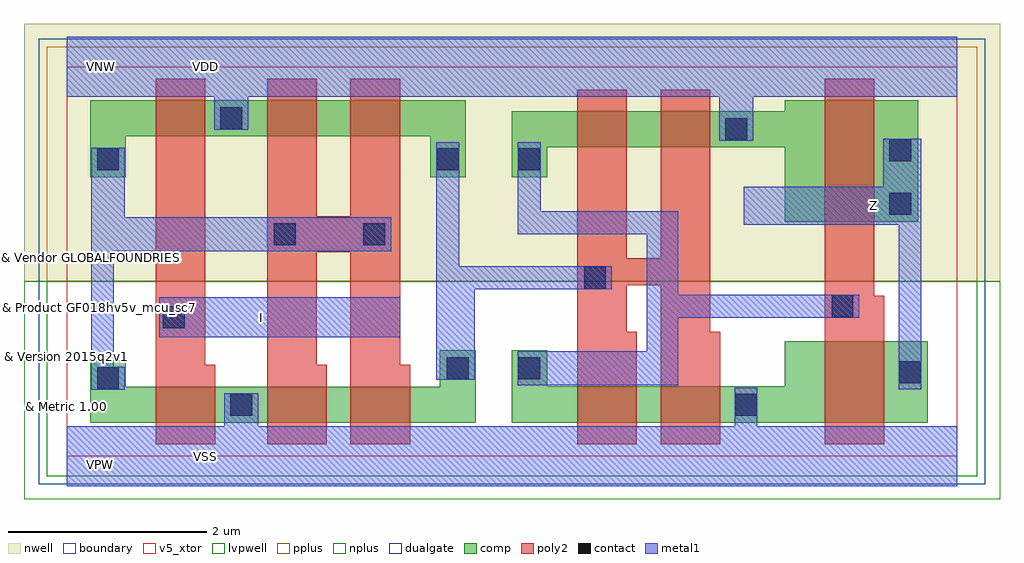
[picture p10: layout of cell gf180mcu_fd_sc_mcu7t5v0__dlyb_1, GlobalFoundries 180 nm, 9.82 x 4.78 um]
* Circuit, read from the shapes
.subckt gf180mcu_fd_sc_mcu7t5v0__dlyb_1 I VDD VNW VSS Z
XM1 VSS I n1 VSUBS nfet_05v0 w=0.36u l=0.6u
XM2 n2 n1 VSS VSUBS nfet_05v0 w=0.36u l=0.6u
XM3 n3 n1 n2 VSUBS nfet_05v0 w=0.36u l=0.6u
XM4 n4 n3 n5 VSUBS nfet_05v0 w=0.365u l=0.6u
XM5 VSS n3 n4 VSUBS nfet_05v0 w=0.365u l=0.6u
XM6 Z n5 VSS VSUBS nfet_05v0 w=0.82u l=0.6u
XM7 VDD I n1 VNW pfet_05v0 w=0.36u l=0.5u
XM8 n6 n1 VDD VNW pfet_05v0 w=0.36u l=0.5u
XM9 n3 n1 n6 VNW pfet_05v0 w=0.36u l=0.5u
XM10 n7 n3 n5 VNW pfet_05v0 w=0.36u l=0.5u
XM11 VDD n3 n7 VNW pfet_05v0 w=0.36u l=0.5u
XM12 Z n5 VDD VNW pfet_05v0 w=1.22u l=0.5u
.ends

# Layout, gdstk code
import gdstk
lib = gdstk.Library(unit=1e-6, precision=1e-09)
def R(c, l, rs):  # rectangles x0, y0, x1, y1
    for r in rs: c.add(gdstk.rectangle(r[:2], r[2:], *l))
def P(c, l, *ps):  # polygons
    for p in ps: c.add(gdstk.Polygon(p, *l))
boundary = (0, 0)
nwell = (21, 0)
comp = (22, 0)
poly2 = (30, 0)
pplus = (31, 0)
nplus = (32, 0)
contact = (33, 0)
metal1 = (34, 0)
dualgate = (55, 0)
v5_xtor = (112, 1)
lvpwell = (204, 0)

gf180mcu_fd_sc_mcu7t5v0_ = lib.new_cell('gf180mcu_fd_sc_mcu7t5v0__dlyb_1')
R(gf180mcu_fd_sc_mcu7t5v0_, boundary, [(0,0,8.96,3.92)])
R(gf180mcu_fd_sc_mcu7t5v0_, nwell, [(-0.43,1.76,9.39,4.35)])
P(gf180mcu_fd_sc_mcu7t5v0_, comp, [(0.235,2.81),(0.235,3.58),(4.015,3.58),(4.015,2.81),(3.655,2.81),(3.655,3.22),(0.595,3.22),(0.595,2.81)],
  [(0.235,0.34),(0.235,0.965),(0.595,0.965),(0.595,0.7),(3.755,0.7),(3.755,1.065),(4.115,1.065),(4.115,0.34)],
  [(7.225,2.36),(7.225,3.11),(4.835,3.11),(4.835,2.81),(4.475,2.81),(4.475,3.47),(7.225,3.47),(7.225,3.58),(8.565,3.58),(8.565,2.36)],
  [(4.475,0.34),(4.475,1.065),(4.835,1.065),(4.835,0.705),(7.225,0.705),(7.225,1.16),(8.665,1.16),(8.665,0.34)])
P(gf180mcu_fd_sc_mcu7t5v0_, poly2, [(0.895,0.12),(0.895,3.8),(1.395,3.8),(1.395,0.92),(1.495,0.92),(1.495,0.12)],
  [(2.015,0.12),(2.015,3.8),(2.515,3.8),(2.515,2.415),(2.855,2.415),(2.855,3.8),(3.355,3.8),(3.355,0.92),(3.455,0.92),(3.455,0.12),(2.855,0.12),(2.855,2.055),(2.515,2.055),(2.515,0.92),(2.615,0.92),(2.615,0.12)],
  [(5.135,0.12),(5.135,3.69),(5.635,3.69),(5.635,1.995),(5.975,1.995),(5.975,3.69),(6.475,3.69),(6.475,1.255),(6.575,1.255),(6.575,0.12),(5.975,0.12),(5.975,1.72),(5.635,1.72),(5.635,1.255),(5.735,1.255),(5.735,0.12)],
  [(7.625,0.12),(7.625,3.8),(8.125,3.8),(8.125,1.615),(8.225,1.615),(8.225,0.12)])
R(gf180mcu_fd_sc_mcu7t5v0_, pplus, [(-0.2,1.76,9.16,4.12)])
R(gf180mcu_fd_sc_mcu7t5v0_, nplus, [(-0.2,-0.2,9.16,1.76)])
R(gf180mcu_fd_sc_mcu7t5v0_, contact, [(1.645,0.41,1.865,0.63), (6.725,0.41,6.945,0.63), (0.305,0.675,0.525,0.895), (8.375,0.735,8.595,0.955), (3.825,0.775,4.045,0.995), (4.545,0.775,4.765,0.995), (0.965,1.29,1.185,1.51), (7.695,1.4,7.915,1.62), (5.205,1.685,5.425,1.905), (2.085,2.125,2.305,2.345), (2.985,2.125,3.205,2.345), (8.275,2.43,8.495,2.65), (0.305,2.88,0.525,3.1), (3.725,2.88,3.945,3.1), (4.545,2.88,4.765,3.1), (8.275,2.97,8.495,3.19), (6.625,3.18,6.845,3.4), (1.545,3.29,1.765,3.51)])
R(gf180mcu_fd_sc_mcu7t5v0_, metal1, [(0.93,1.2,3.355,1.6)])
P(gf180mcu_fd_sc_mcu7t5v0_, metal1, [(0.245,0.67),(0.245,3.105),(0.585,3.105),(0.585,2.405),(3.265,2.405),(3.265,2.065),(0.475,2.065),(0.475,0.9),(0.585,0.9),(0.585,0.67)],
  [(3.72,0.77),(3.72,3.16),(3.95,3.16),(3.95,1.91),(5.485,1.91),(5.485,1.68),(4.105,1.68),(4.105,0.77)],
  [(4.54,0.715),(4.54,1.055),(5.835,1.055),(5.835,2.235),(4.54,2.235),(4.54,3.16),(4.77,3.16),(4.77,2.465),(6.155,2.465),(6.155,1.625),(7.975,1.625),(7.975,1.395),(6.155,1.395),(6.155,0.715)],
  [(8.37,0.675),(8.37,2.33),(6.81,2.33),(6.81,2.71),(8.215,2.71),(8.215,3.195),(8.6,3.195),(8.6,0.675)],
  [(0,-0.3),(0,0.3),(1.585,0.3),(1.585,0.635),(1.925,0.635),(1.925,0.3),(6.72,0.3),(6.72,0.69),(6.95,0.69),(6.95,0.3),(8.96,0.3),(8.96,-0.3)],
  [(6.565,3.175),(6.565,3.62),(1.825,3.62),(1.825,3.285),(1.485,3.285),(1.485,3.62),(0,3.62),(0,4.22),(8.96,4.22),(8.96,3.62),(6.905,3.62),(6.905,3.175)])
R(gf180mcu_fd_sc_mcu7t5v0_, dualgate, [(-0.28,-0.28,9.24,4.2)])
R(gf180mcu_fd_sc_mcu7t5v0_, v5_xtor, [(0,0,8.96,3.92)])
R(gf180mcu_fd_sc_mcu7t5v0_, lvpwell, [(-0.43,-0.43,9.39,1.76)])
gf180mcu_fd_sc_mcu7t5v0_.add(gdstk.Label('VDD', (1.4,3.92), layer=34, texttype=10))
gf180mcu_fd_sc_mcu7t5v0_.add(gdstk.Label('I', (1.96,1.4), layer=34, texttype=10))
gf180mcu_fd_sc_mcu7t5v0_.add(gdstk.Label('VSS', (1.4,0), layer=34, texttype=10))
gf180mcu_fd_sc_mcu7t5v0_.add(gdstk.Label('Z', (8.12,2.52), layer=34, texttype=10))
gf180mcu_fd_sc_mcu7t5v0_.add(gdstk.Label('& Vendor GLOBALFOUNDRIES', (0,2), layer=63, texttype=63))
gf180mcu_fd_sc_mcu7t5v0_.add(gdstk.Label('& Product GF018hv5v_mcu_sc7', (0,1.5), layer=63, texttype=63))
gf180mcu_fd_sc_mcu7t5v0_.add(gdstk.Label('& Version 2015q2v1', (0,1), layer=63, texttype=63))
gf180mcu_fd_sc_mcu7t5v0_.add(gdstk.Label('& Metric 1.00', (0,0.5), layer=63, texttype=63))
gf180mcu_fd_sc_mcu7t5v0_.add(gdstk.Label('VNW', (0.345,3.92), layer=21, texttype=10))
gf180mcu_fd_sc_mcu7t5v0_.add(gdstk.Label('VPW', (0.34,-0.085), layer=204, texttype=10))

lib.write_gds('gf180mcu_fd_sc_mcu7t5v0__dlyb_1.gds')
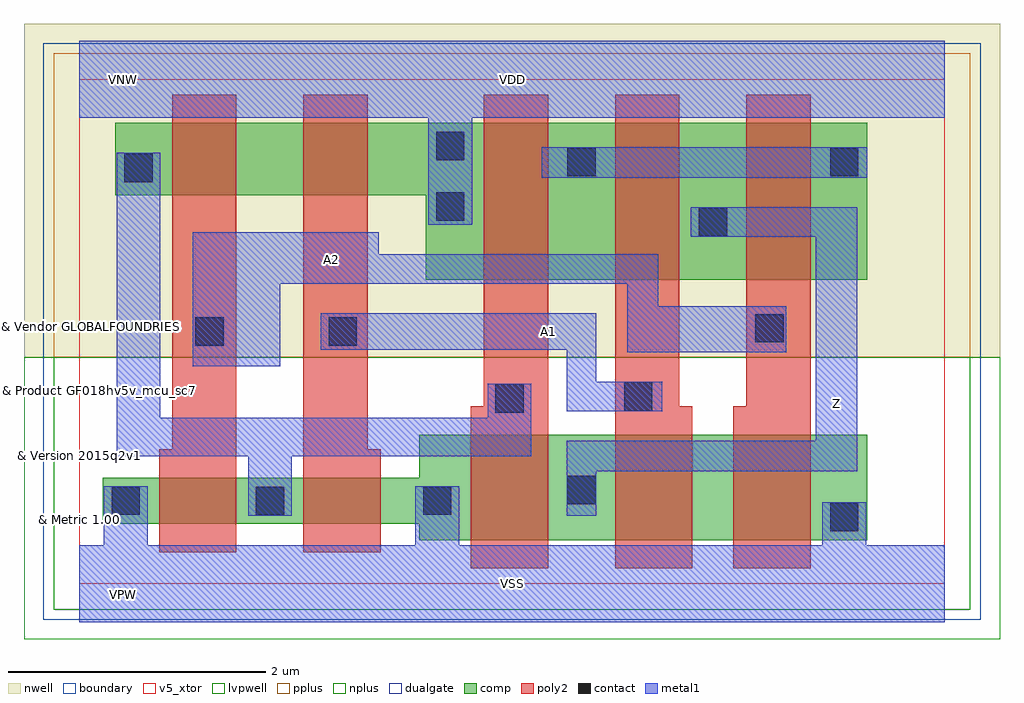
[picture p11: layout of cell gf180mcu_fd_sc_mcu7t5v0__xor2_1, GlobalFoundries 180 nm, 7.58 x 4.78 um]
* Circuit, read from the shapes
.subckt gf180mcu_fd_sc_mcu7t5v0__xor2_1 A1 A2 VDD VNW VSS Z
XM1 n1 A2 VSS VSUBS nfet_05v0 w=0.36u l=0.6u
XM2 VSS A1 n1 VSUBS nfet_05v0 w=0.36u l=0.6u
XM3 Z n1 VSS VSUBS nfet_05v0 w=0.82u l=0.6u
XM4 n2 A1 Z VSUBS nfet_05v0 w=0.82u l=0.6u
XM5 VSS A2 n2 VSUBS nfet_05v0 w=0.82u l=0.6u
XM6 n3 A2 n1 VNW pfet_05v0 w=0.56u l=0.5u
XM7 VDD A1 n3 VNW pfet_05v0 w=0.56u l=0.5u
XM8 n4 n1 VDD VNW pfet_05v0 w=1.22u l=0.5u
XM9 Z A1 n4 VNW pfet_05v0 w=1.22u l=0.5u
XM10 n4 A2 Z VNW pfet_05v0 w=1.22u l=0.5u
.ends

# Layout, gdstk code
import gdstk
lib = gdstk.Library(unit=1e-6, precision=1e-09)
def R(c, l, rs):  # rectangles x0, y0, x1, y1
    for r in rs: c.add(gdstk.rectangle(r[:2], r[2:], *l))
def P(c, l, *ps):  # polygons
    for p in ps: c.add(gdstk.Polygon(p, *l))
boundary = (0, 0)
nwell = (21, 0)
comp = (22, 0)
poly2 = (30, 0)
pplus = (31, 0)
nplus = (32, 0)
contact = (33, 0)
metal1 = (34, 0)
dualgate = (55, 0)
v5_xtor = (112, 1)
lvpwell = (204, 0)

gf180mcu_fd_sc_mcu7t5v0_ = lib.new_cell('gf180mcu_fd_sc_mcu7t5v0__xor2_1')
R(gf180mcu_fd_sc_mcu7t5v0_, boundary, [(0,0,6.72,3.92)])
R(gf180mcu_fd_sc_mcu7t5v0_, nwell, [(-0.43,1.76,7.15,4.35)])
P(gf180mcu_fd_sc_mcu7t5v0_, comp, [(2.64,0.34),(2.64,0.465),(0.18,0.465),(0.18,0.825),(2.64,0.825),(2.64,1.16),(6.12,1.16),(6.12,0.34)],
  [(2.69,2.36),(2.69,3.02),(0.28,3.02),(0.28,3.58),(6.12,3.58),(6.12,2.36)])
P(gf180mcu_fd_sc_mcu7t5v0_, poly2, [(0.62,0.245),(0.62,1.045),(0.72,1.045),(0.72,3.8),(1.22,3.8),(1.22,0.245)],
  [(1.74,0.245),(1.74,3.8),(2.24,3.8),(2.24,1.045),(2.34,1.045),(2.34,0.245)],
  [(3.04,0.12),(3.04,1.38),(3.14,1.38),(3.14,3.8),(3.64,3.8),(3.64,0.12)],
  [(4.16,0.12),(4.16,3.8),(4.66,3.8),(4.66,1.38),(4.76,1.38),(4.76,0.12)],
  [(5.08,0.12),(5.08,1.38),(5.18,1.38),(5.18,3.8),(5.68,3.8),(5.68,0.12)])
R(gf180mcu_fd_sc_mcu7t5v0_, pplus, [(-0.2,1.76,6.92,4.12)])
R(gf180mcu_fd_sc_mcu7t5v0_, nplus, [(-0.2,-0.2,6.92,1.76)])
R(gf180mcu_fd_sc_mcu7t5v0_, contact, [(5.83,0.41,6.05,0.63), (0.25,0.535,0.47,0.755), (1.37,0.535,1.59,0.755), (2.67,0.535,2.89,0.755), (3.79,0.62,4.01,0.84), (3.23,1.33,3.45,1.55), (4.23,1.345,4.45,1.565), (0.9,1.85,1.12,2.07), (1.935,1.85,2.155,2.07), (5.25,1.875,5.47,2.095), (4.81,2.7,5.03,2.92), (2.77,2.82,2.99,3.04), (0.35,3.12,0.57,3.34), (3.79,3.165,4.01,3.385), (5.83,3.165,6.05,3.385), (2.77,3.29,2.99,3.51)])
R(gf180mcu_fd_sc_mcu7t5v0_, metal1, [(3.59,3.155,6.12,3.39)])
P(gf180mcu_fd_sc_mcu7t5v0_, metal1, [(1.31,0.53),(1.31,0.99),(0.29,0.99),(0.29,3.35),(0.63,3.35),(0.63,1.29),(3.17,1.29),(3.17,1.555),(3.51,1.555),(3.51,0.99),(1.65,0.99),(1.65,0.53)],
  [(3.785,1.34),(3.785,1.82),(1.875,1.82),(1.875,2.1),(4.015,2.1),(4.015,1.57),(4.525,1.57),(4.525,1.34)],
  [(0.88,1.69),(0.88,2.73),(2.325,2.73),(2.325,2.56),(4.495,2.56),(4.495,2.155),(5.49,2.155),(5.49,1.8),(4.255,1.8),(4.255,2.33),(1.56,2.33),(1.56,1.69)],
  [(3.785,0.53),(3.785,1.11),(5.72,1.11),(5.72,2.695),(4.75,2.695),(4.75,2.925),(6.04,2.925),(6.04,0.875),(4.015,0.875),(4.015,0.53)],
  [(0,-0.3),(0,0.3),(0.19,0.3),(0.19,0.76),(0.53,0.76),(0.53,0.3),(2.61,0.3),(2.61,0.76),(2.95,0.76),(2.95,0.3),(5.77,0.3),(5.77,0.635),(6.11,0.635),(6.11,0.3),(6.72,0.3),(6.72,-0.3)],
  [(2.71,2.79),(2.71,3.62),(0,3.62),(0,4.22),(6.72,4.22),(6.72,3.62),(3.05,3.62),(3.05,2.79)])
R(gf180mcu_fd_sc_mcu7t5v0_, dualgate, [(-0.28,-0.28,7,4.2)])
R(gf180mcu_fd_sc_mcu7t5v0_, v5_xtor, [(0,0,6.72,3.92)])
R(gf180mcu_fd_sc_mcu7t5v0_, lvpwell, [(-0.43,-0.43,7.15,1.76)])
gf180mcu_fd_sc_mcu7t5v0_.add(gdstk.Label('VDD', (3.36,3.915), layer=34, texttype=10))
gf180mcu_fd_sc_mcu7t5v0_.add(gdstk.Label('VSS', (3.36,0), layer=34, texttype=10))
gf180mcu_fd_sc_mcu7t5v0_.add(gdstk.Label('Z', (5.88,1.4), layer=34, texttype=10))
gf180mcu_fd_sc_mcu7t5v0_.add(gdstk.Label('A1', (3.64,1.96), layer=34, texttype=10))
gf180mcu_fd_sc_mcu7t5v0_.add(gdstk.Label('A2', (1.96,2.52), layer=34, texttype=10))
gf180mcu_fd_sc_mcu7t5v0_.add(gdstk.Label('& Vendor GLOBALFOUNDRIES', (0,2), layer=63, texttype=63))
gf180mcu_fd_sc_mcu7t5v0_.add(gdstk.Label('& Product GF018hv5v_mcu_sc7', (0,1.5), layer=63, texttype=63))
gf180mcu_fd_sc_mcu7t5v0_.add(gdstk.Label('& Version 2015q2v1', (0,1), layer=63, texttype=63))
gf180mcu_fd_sc_mcu7t5v0_.add(gdstk.Label('& Metric 1.00', (0,0.5), layer=63, texttype=63))
gf180mcu_fd_sc_mcu7t5v0_.add(gdstk.Label('VNW', (0.345,3.92), layer=21, texttype=10))
gf180mcu_fd_sc_mcu7t5v0_.add(gdstk.Label('VPW', (0.34,-0.085), layer=204, texttype=10))

lib.write_gds('gf180mcu_fd_sc_mcu7t5v0__xor2_1.gds')
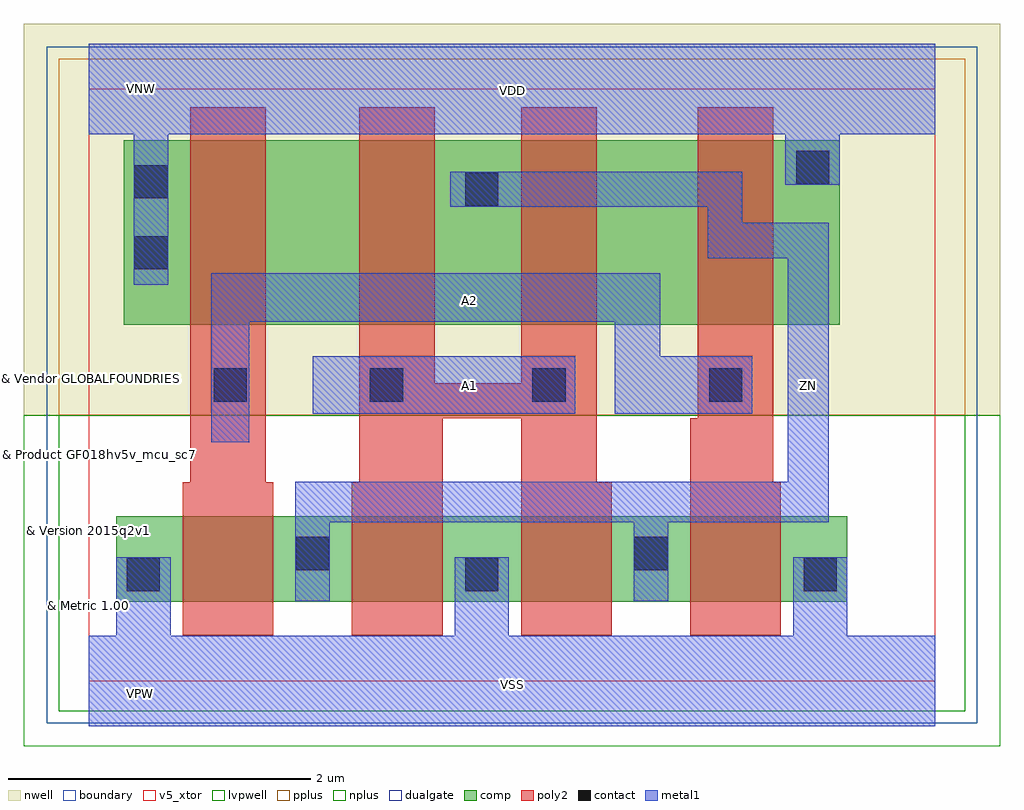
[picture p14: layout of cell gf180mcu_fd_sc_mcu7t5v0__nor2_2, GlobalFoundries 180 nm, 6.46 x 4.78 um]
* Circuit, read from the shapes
.subckt gf180mcu_fd_sc_mcu7t5v0__nor2_2 A1 A2 VDD VNW VSS ZN
XM1 ZN A2 VSS VSUBS nfet_05v0 w=0.565u l=0.6u m=2
XM2 VSS A1 ZN VSUBS nfet_05v0 w=0.565u l=0.6u m=2
XM3 n1 A2 VDD VNW pfet_05v0 w=1.22u l=0.5u
XM4 ZN A1 n1 VNW pfet_05v0 w=1.22u l=0.5u
XM5 n2 A1 ZN VNW pfet_05v0 w=1.22u l=0.5u
XM6 VDD A2 n2 VNW pfet_05v0 w=1.22u l=0.5u
.ends

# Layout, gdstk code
import gdstk
lib = gdstk.Library(unit=1e-6, precision=1e-09)
def R(c, l, rs):  # rectangles x0, y0, x1, y1
    for r in rs: c.add(gdstk.rectangle(r[:2], r[2:], *l))
def A(c, l, x, y, w, h, nx, ny, dx, dy):  # array of equal rectangles
    R(c, l, [(x+i*dx, y+j*dy, x+i*dx+w, y+j*dy+h) for i in range(nx) for j in range(ny)])
def P(c, l, *ps):  # polygons
    for p in ps: c.add(gdstk.Polygon(p, *l))
boundary = (0, 0)
nwell = (21, 0)
comp = (22, 0)
poly2 = (30, 0)
pplus = (31, 0)
nplus = (32, 0)
contact = (33, 0)
metal1 = (34, 0)
dualgate = (55, 0)
v5_xtor = (112, 1)
lvpwell = (204, 0)

gf180mcu_fd_sc_mcu7t5v0_ = lib.new_cell('gf180mcu_fd_sc_mcu7t5v0__nor2_2')
R(gf180mcu_fd_sc_mcu7t5v0_, boundary, [(0,0,5.6,3.92)])
R(gf180mcu_fd_sc_mcu7t5v0_, nwell, [(-0.43,1.76,6.03,4.35)])
R(gf180mcu_fd_sc_mcu7t5v0_, comp, [(0.18,0.525,5.02,1.09), (0.23,2.36,4.97,3.58)])
P(gf180mcu_fd_sc_mcu7t5v0_, poly2, [(0.62,0.305),(0.62,1.315),(0.67,1.315),(0.67,3.8),(1.17,3.8),(1.17,1.315),(1.22,1.315),(1.22,0.305)],
  [(1.74,0.305),(1.74,1.315),(1.79,1.315),(1.79,3.8),(2.29,3.8),(2.29,1.97),(2.86,1.97),(2.86,3.8),(3.36,3.8),(3.36,1.315),(3.46,1.315),(3.46,0.305),(2.86,0.305),(2.86,1.74),(2.34,1.74),(2.34,0.305)],
  [(3.98,0.305),(3.98,1.74),(4.03,1.74),(4.03,3.8),(4.53,3.8),(4.53,1.315),(4.58,1.315),(4.58,0.305)])
R(gf180mcu_fd_sc_mcu7t5v0_, pplus, [(-0.2,1.76,5.8,4.12)])
R(gf180mcu_fd_sc_mcu7t5v0_, nplus, [(-0.2,-0.2,5.8,1.76)])
A(gf180mcu_fd_sc_mcu7t5v0_, contact, 0.25, 0.595, 0.22, 0.22, 3, 1, 2.24, 0)
R(gf180mcu_fd_sc_mcu7t5v0_, contact, [(1.37,0.735,1.59,0.955), (3.61,0.735,3.83,0.955), (0.825,1.85,1.045,2.07), (1.86,1.85,2.08,2.07), (2.935,1.85,3.155,2.07), (4.105,1.85,4.325,2.07), (0.3,2.725,0.52,2.945), (2.49,3.145,2.71,3.365), (0.3,3.195,0.52,3.415), (4.68,3.29,4.9,3.51)])
R(gf180mcu_fd_sc_mcu7t5v0_, metal1, [(1.48,1.77,3.22,2.15)])
P(gf180mcu_fd_sc_mcu7t5v0_, metal1, [(0.81,1.58),(0.81,2.7),(3.78,2.7),(3.78,2.15),(4.39,2.15),(4.39,1.77),(3.48,1.77),(3.48,2.38),(1.06,2.38),(1.06,1.58)],
  [(1.365,0.53),(1.365,1.32),(4.625,1.32),(4.625,2.8),(4.095,2.8),(4.095,3.14),(2.39,3.14),(2.39,3.37),(4.325,3.37),(4.325,3.035),(4.895,3.035),(4.895,1.05),(3.835,1.05),(3.835,0.53),(3.605,0.53),(3.605,1.05),(1.595,1.05),(1.595,0.53)],
  [(0,-0.3),(0,0.3),(0.18,0.3),(0.18,0.82),(0.54,0.82),(0.54,0.3),(2.42,0.3),(2.42,0.82),(2.78,0.82),(2.78,0.3),(4.66,0.3),(4.66,0.82),(5.02,0.82),(5.02,0.3),(5.6,0.3),(5.6,-0.3)],
  [(0.295,2.625),(0.295,3.62),(0,3.62),(0,4.22),(5.6,4.22),(5.6,3.62),(4.97,3.62),(4.97,3.285),(4.61,3.285),(4.61,3.62),(0.525,3.62),(0.525,2.625)])
R(gf180mcu_fd_sc_mcu7t5v0_, dualgate, [(-0.28,-0.28,5.88,4.2)])
R(gf180mcu_fd_sc_mcu7t5v0_, v5_xtor, [(0,0,5.6,3.92)])
R(gf180mcu_fd_sc_mcu7t5v0_, lvpwell, [(-0.43,-0.43,6.03,1.76)])
gf180mcu_fd_sc_mcu7t5v0_.add(gdstk.Label('VDD', (2.8,3.91), layer=34, texttype=10))
gf180mcu_fd_sc_mcu7t5v0_.add(gdstk.Label('VSS', (2.8,-0.025), layer=34, texttype=10))
gf180mcu_fd_sc_mcu7t5v0_.add(gdstk.Label('ZN', (4.76,1.96), layer=34, texttype=10))
gf180mcu_fd_sc_mcu7t5v0_.add(gdstk.Label('A1', (2.52,1.96), layer=34, texttype=10))
gf180mcu_fd_sc_mcu7t5v0_.add(gdstk.Label('A2', (2.52,2.52), layer=34, texttype=10))
gf180mcu_fd_sc_mcu7t5v0_.add(gdstk.Label('& Vendor GLOBALFOUNDRIES', (0,2), layer=63, texttype=63))
gf180mcu_fd_sc_mcu7t5v0_.add(gdstk.Label('& Product GF018hv5v_mcu_sc7', (0,1.5), layer=63, texttype=63))
gf180mcu_fd_sc_mcu7t5v0_.add(gdstk.Label('& Version 2015q2v1', (0,1), layer=63, texttype=63))
gf180mcu_fd_sc_mcu7t5v0_.add(gdstk.Label('& Metric 1.00', (0,0.5), layer=63, texttype=63))
gf180mcu_fd_sc_mcu7t5v0_.add(gdstk.Label('VNW', (0.345,3.92), layer=21, texttype=10))
gf180mcu_fd_sc_mcu7t5v0_.add(gdstk.Label('VPW', (0.34,-0.085), layer=204, texttype=10))

lib.write_gds('gf180mcu_fd_sc_mcu7t5v0__nor2_2.gds')
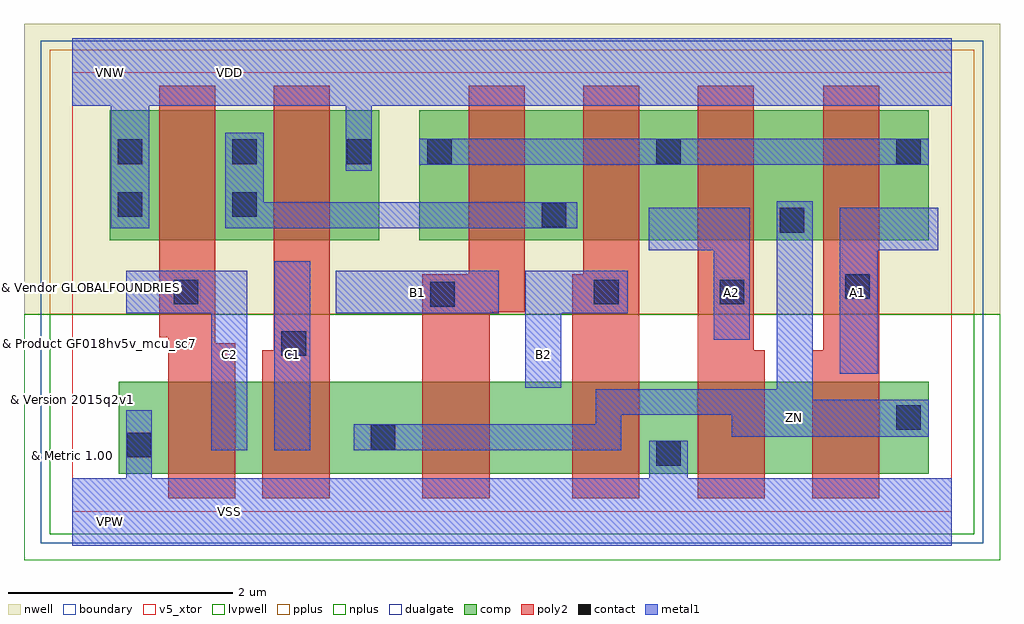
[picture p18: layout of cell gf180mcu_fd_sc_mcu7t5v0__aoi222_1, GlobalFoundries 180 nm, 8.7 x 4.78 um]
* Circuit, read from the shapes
.subckt gf180mcu_fd_sc_mcu7t5v0__aoi222_1 A1 A2 B1 B2 C1 C2 VDD VNW VSS ZN
XM1 n1 C2 VSS VSUBS nfet_05v0 w=0.82u l=0.6u
XM2 ZN C1 n1 VSUBS nfet_05v0 w=0.82u l=0.6u
XM3 n2 B1 ZN VSUBS nfet_05v0 w=0.82u l=0.6u
XM4 VSS B2 n2 VSUBS nfet_05v0 w=0.82u l=0.6u
XM5 n3 A2 VSS VSUBS nfet_05v0 w=0.82u l=0.6u
XM6 ZN A1 n3 VSUBS nfet_05v0 w=0.82u l=0.6u
XM7 n4 C2 VDD VNW pfet_05v0 w=1.16u l=0.5u
XM8 VDD C1 n4 VNW pfet_05v0 w=1.16u l=0.5u
XM9 n4 B1 n5 VNW pfet_05v0 w=1.16u l=0.5u
XM10 n5 B2 n4 VNW pfet_05v0 w=1.16u l=0.5u
XM11 ZN A2 n5 VNW pfet_05v0 w=1.16u l=0.5u
XM12 n5 A1 ZN VNW pfet_05v0 w=1.16u l=0.5u
.ends

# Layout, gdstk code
import gdstk
lib = gdstk.Library(unit=1e-6, precision=1e-09)
def R(c, l, rs):  # rectangles x0, y0, x1, y1
    for r in rs: c.add(gdstk.rectangle(r[:2], r[2:], *l))
def A(c, l, x, y, w, h, nx, ny, dx, dy):  # array of equal rectangles
    R(c, l, [(x+i*dx, y+j*dy, x+i*dx+w, y+j*dy+h) for i in range(nx) for j in range(ny)])
def P(c, l, *ps):  # polygons
    for p in ps: c.add(gdstk.Polygon(p, *l))
boundary = (0, 0)
nwell = (21, 0)
comp = (22, 0)
poly2 = (30, 0)
pplus = (31, 0)
nplus = (32, 0)
contact = (33, 0)
metal1 = (34, 0)
dualgate = (55, 0)
v5_xtor = (112, 1)
lvpwell = (204, 0)

gf180mcu_fd_sc_mcu7t5v0_ = lib.new_cell('gf180mcu_fd_sc_mcu7t5v0__aoi222_1')
R(gf180mcu_fd_sc_mcu7t5v0_, boundary, [(0,0,7.84,3.92)])
R(gf180mcu_fd_sc_mcu7t5v0_, nwell, [(-0.43,1.76,8.27,4.35)])
R(gf180mcu_fd_sc_mcu7t5v0_, comp, [(0.415,0.34,7.635,1.16), (0.335,2.42,2.735,3.58), (3.095,2.42,7.635,3.58)])
P(gf180mcu_fd_sc_mcu7t5v0_, poly2, [(0.855,0.12),(0.855,1.555),(0.775,1.555),(0.775,3.8),(1.275,3.8),(1.275,1.505),(1.455,1.505),(1.455,0.12)],
  [(1.695,0.12),(1.695,1.44),(1.795,1.44),(1.795,3.8),(2.295,3.8),(2.295,0.12)],
  [(3.12,0.12),(3.12,2.12),(3.535,2.12),(3.535,3.8),(4.035,3.8),(4.035,1.78),(3.72,1.78),(3.72,0.12)],
  [(4.455,0.12),(4.455,2.12),(4.555,2.12),(4.555,3.8),(5.055,3.8),(5.055,0.12)],
  [(5.575,0.12),(5.575,3.8),(6.075,3.8),(6.075,1.44),(6.175,1.44),(6.175,0.12)],
  [(6.595,0.12),(6.595,1.44),(6.695,1.44),(6.695,3.8),(7.195,3.8),(7.195,0.12)])
R(gf180mcu_fd_sc_mcu7t5v0_, pplus, [(-0.2,1.76,8.04,4.12)])
R(gf180mcu_fd_sc_mcu7t5v0_, nplus, [(-0.2,-0.2,8.04,1.76)])
A(gf180mcu_fd_sc_mcu7t5v0_, contact, 0.405, 3.1, 0.22, 0.22, 3, 1, 1.02, 0)
R(gf180mcu_fd_sc_mcu7t5v0_, contact, [(5.205,0.41,5.425,0.63), (0.485,0.485,0.705,0.705), (2.66,0.555,2.88,0.775), (7.345,0.73,7.565,0.95), (1.865,1.39,2.085,1.61), (3.19,1.83,3.41,2.05), (0.905,1.85,1.125,2.07), (4.65,1.85,4.87,2.07), (5.77,1.85,5.99,2.07), (6.89,1.9,7.11,2.12), (6.305,2.49,6.525,2.71), (4.185,2.535,4.405,2.755), (0.405,2.63,0.625,2.85), (1.425,2.63,1.645,2.85), (3.165,3.1,3.385,3.32), (5.205,3.1,5.425,3.32), (7.345,3.1,7.565,3.32)])
R(gf180mcu_fd_sc_mcu7t5v0_, metal1, [(1.8,0.55,2.12,2.235), (2.35,1.77,3.8,2.15), (3.095,3.095,7.635,3.325)])
P(gf180mcu_fd_sc_mcu7t5v0_, metal1, [(1.24,0.55),(1.24,1.77),(0.48,1.77),(0.48,2.15),(1.56,2.15),(1.56,0.55)],
  [(1.365,2.53),(1.365,3.38),(1.705,3.38),(1.705,2.76),(4.5,2.76),(4.5,2.53)],
  [(4.04,1.105),(4.04,2.15),(4.95,2.15),(4.95,1.77),(4.36,1.77),(4.36,1.105)],
  [(5.72,1.535),(5.72,2.33),(5.14,2.33),(5.14,2.71),(6.04,2.71),(6.04,1.535)],
  [(2.51,0.55),(2.51,0.78),(4.665,0.78),(4.665,1.095),(6.28,1.095),(6.28,2.77),(6.6,2.77),(6.6,1),(7.635,1),(7.635,0.67),(5.88,0.67),(5.88,0.865),(4.895,0.865),(4.895,0.55)],
  [(6.84,1.23),(6.84,2.71),(7.72,2.71),(7.72,2.33),(7.18,2.33),(7.18,1.23)],
  [(0,-0.3),(0,0.3),(0.48,0.3),(0.48,0.905),(0.71,0.905),(0.71,0.3),(5.145,0.3),(5.145,0.635),(5.485,0.635),(5.485,0.3),(7.84,0.3),(7.84,-0.3)],
  [(0.345,2.53),(0.345,3.62),(0,3.62),(0,4.22),(7.84,4.22),(7.84,3.62),(2.67,3.62),(2.67,3.04),(2.44,3.04),(2.44,3.62),(0.685,3.62),(0.685,2.53)])
R(gf180mcu_fd_sc_mcu7t5v0_, dualgate, [(-0.28,-0.28,8.12,4.2)])
R(gf180mcu_fd_sc_mcu7t5v0_, v5_xtor, [(0,0,7.84,3.92)])
R(gf180mcu_fd_sc_mcu7t5v0_, lvpwell, [(-0.43,-0.43,8.27,1.76)])
gf180mcu_fd_sc_mcu7t5v0_.add(gdstk.Label('VSS', (1.4,0), layer=34, texttype=10))
gf180mcu_fd_sc_mcu7t5v0_.add(gdstk.Label('VDD', (1.4,3.92), layer=34, texttype=10))
gf180mcu_fd_sc_mcu7t5v0_.add(gdstk.Label('C2', (1.4,1.4), layer=34, texttype=10))
gf180mcu_fd_sc_mcu7t5v0_.add(gdstk.Label('C1', (1.96,1.4), layer=34, texttype=10))
gf180mcu_fd_sc_mcu7t5v0_.add(gdstk.Label('B2', (4.2,1.4), layer=34, texttype=10))
gf180mcu_fd_sc_mcu7t5v0_.add(gdstk.Label('B1', (3.08,1.96), layer=34, texttype=10))
gf180mcu_fd_sc_mcu7t5v0_.add(gdstk.Label('A2', (5.88,1.96), layer=34, texttype=10))
gf180mcu_fd_sc_mcu7t5v0_.add(gdstk.Label('A1', (7,1.96), layer=34, texttype=10))
gf180mcu_fd_sc_mcu7t5v0_.add(gdstk.Label('ZN', (6.44,0.84), layer=34, texttype=10))
gf180mcu_fd_sc_mcu7t5v0_.add(gdstk.Label('& Vendor GLOBALFOUNDRIES', (0,2), layer=63, texttype=63))
gf180mcu_fd_sc_mcu7t5v0_.add(gdstk.Label('& Product GF018hv5v_mcu_sc7', (0,1.5), layer=63, texttype=63))
gf180mcu_fd_sc_mcu7t5v0_.add(gdstk.Label('& Version 2015q2v1', (0,1), layer=63, texttype=63))
gf180mcu_fd_sc_mcu7t5v0_.add(gdstk.Label('& Metric 1.00', (0,0.5), layer=63, texttype=63))
gf180mcu_fd_sc_mcu7t5v0_.add(gdstk.Label('VNW', (0.345,3.92), layer=21, texttype=10))
gf180mcu_fd_sc_mcu7t5v0_.add(gdstk.Label('VPW', (0.34,-0.085), layer=204, texttype=10))

lib.write_gds('gf180mcu_fd_sc_mcu7t5v0__aoi222_1.gds')
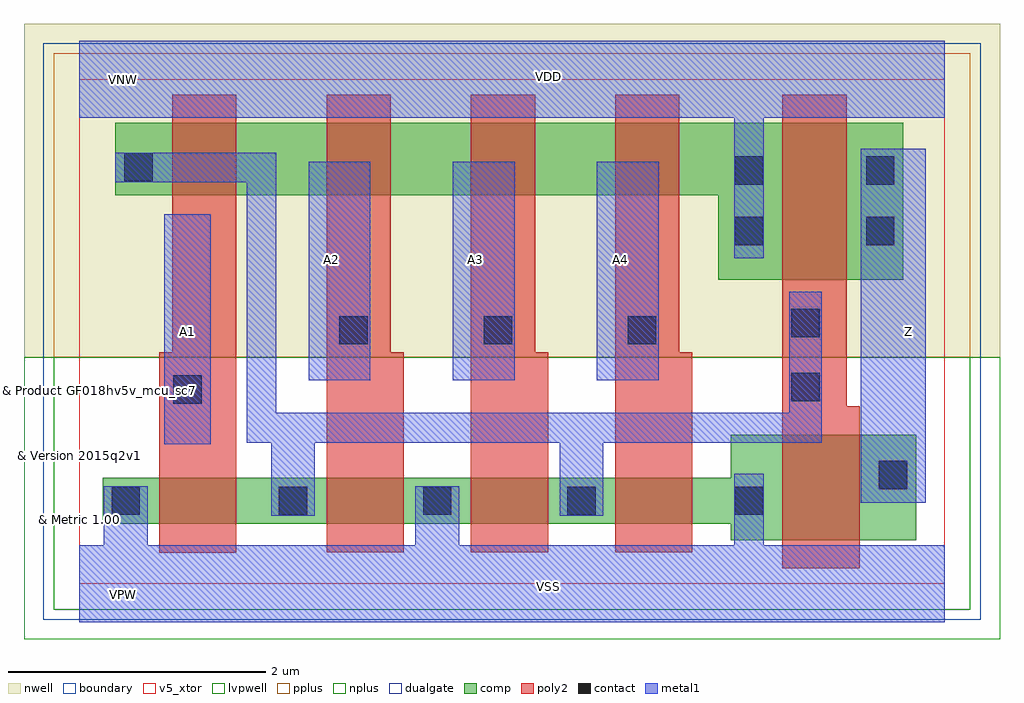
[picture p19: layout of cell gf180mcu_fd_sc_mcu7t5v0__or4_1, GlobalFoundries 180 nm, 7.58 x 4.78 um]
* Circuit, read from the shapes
.subckt gf180mcu_fd_sc_mcu7t5v0__or4_1 A1 A2 A3 A4 VDD VNW VSS Z
XM1 n1 A1 VSS VSUBS nfet_05v0 w=0.36u l=0.6u
XM2 VSS A2 n1 VSUBS nfet_05v0 w=0.36u l=0.6u
XM3 n1 A3 VSS VSUBS nfet_05v0 w=0.36u l=0.6u
XM4 VSS A4 n1 VSUBS nfet_05v0 w=0.36u l=0.6u
XM5 Z n1 VSS VSUBS nfet_05v0 w=0.82u l=0.6u
XM6 n2 A1 n1 VNW pfet_05v0 w=0.56u l=0.5u
XM7 n3 A2 n2 VNW pfet_05v0 w=0.56u l=0.5u
XM8 n4 A3 n3 VNW pfet_05v0 w=0.56u l=0.5u
XM9 VDD A4 n4 VNW pfet_05v0 w=0.56u l=0.5u
XM10 Z n1 VDD VNW pfet_05v0 w=1.22u l=0.5u
.ends

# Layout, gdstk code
import gdstk
lib = gdstk.Library(unit=1e-6, precision=1e-09)
def R(c, l, rs):  # rectangles x0, y0, x1, y1
    for r in rs: c.add(gdstk.rectangle(r[:2], r[2:], *l))
def A(c, l, x, y, w, h, nx, ny, dx, dy):  # array of equal rectangles
    R(c, l, [(x+i*dx, y+j*dy, x+i*dx+w, y+j*dy+h) for i in range(nx) for j in range(ny)])
def P(c, l, *ps):  # polygons
    for p in ps: c.add(gdstk.Polygon(p, *l))
boundary = (0, 0)
nwell = (21, 0)
comp = (22, 0)
poly2 = (30, 0)
pplus = (31, 0)
nplus = (32, 0)
contact = (33, 0)
metal1 = (34, 0)
dualgate = (55, 0)
v5_xtor = (112, 1)
lvpwell = (204, 0)

gf180mcu_fd_sc_mcu7t5v0_ = lib.new_cell('gf180mcu_fd_sc_mcu7t5v0__or4_1')
R(gf180mcu_fd_sc_mcu7t5v0_, boundary, [(0,0,6.72,3.92)])
R(gf180mcu_fd_sc_mcu7t5v0_, nwell, [(-0.43,1.76,7.15,4.35)])
P(gf180mcu_fd_sc_mcu7t5v0_, comp, [(4.96,2.36),(4.96,3.02),(0.28,3.02),(0.28,3.58),(6.4,3.58),(6.4,2.36)],
  [(5.06,0.34),(5.06,0.465),(0.18,0.465),(0.18,0.825),(5.06,0.825),(5.06,1.16),(6.5,1.16),(6.5,0.34)])
P(gf180mcu_fd_sc_mcu7t5v0_, poly2, [(0.62,0.24),(0.62,1.8),(0.72,1.8),(0.72,3.8),(1.22,3.8),(1.22,0.24)],
  [(1.92,0.245),(1.92,3.8),(2.42,3.8),(2.42,1.8),(2.52,1.8),(2.52,0.245)],
  [(3.04,0.245),(3.04,3.8),(3.54,3.8),(3.54,1.8),(3.64,1.8),(3.64,0.245)],
  [(4.16,0.245),(4.16,3.8),(4.66,3.8),(4.66,1.8),(4.76,1.8),(4.76,0.245)],
  [(5.46,0.12),(5.46,3.8),(5.96,3.8),(5.96,1.38),(6.06,1.38),(6.06,0.12)])
R(gf180mcu_fd_sc_mcu7t5v0_, pplus, [(-0.2,1.76,6.92,4.12)])
R(gf180mcu_fd_sc_mcu7t5v0_, nplus, [(-0.2,-0.2,6.92,1.76)])
A(gf180mcu_fd_sc_mcu7t5v0_, contact, 1.55, 0.535, 0.22, 0.22, 3, 1, 1.12, 0)
A(gf180mcu_fd_sc_mcu7t5v0_, contact, 2.02, 1.86, 0.22, 0.22, 3, 1, 1.12, 0)
R(gf180mcu_fd_sc_mcu7t5v0_, contact, [(0.25,0.535,0.47,0.755), (5.09,0.535,5.31,0.755), (6.21,0.735,6.43,0.955), (0.73,1.4,0.95,1.62), (5.53,1.42,5.75,1.64), (5.53,1.915,5.75,2.135), (5.09,2.63,5.31,2.85), (6.11,2.63,6.33,2.85), (5.09,3.1,5.31,3.32), (6.11,3.1,6.33,3.32), (0.35,3.125,0.57,3.345)])
A(gf180mcu_fd_sc_mcu7t5v0_, metal1, 1.78, 1.58, 0.48, 1.7, 3, 1, 1.12, 0)
R(gf180mcu_fd_sc_mcu7t5v0_, metal1, [(6.07,0.63,6.575,3.38), (0.66,1.085,1.02,2.87)])
P(gf180mcu_fd_sc_mcu7t5v0_, metal1, [(1.49,0.53),(1.49,1.095),(1.3,1.095),(1.3,3.12),(0.28,3.12),(0.28,3.35),(1.53,3.35),(1.53,1.33),(5.515,1.33),(5.515,2.27),(5.765,2.27),(5.765,1.095),(4.07,1.095),(4.07,0.53),(3.73,0.53),(3.73,1.095),(1.83,1.095),(1.83,0.53)],
  [(0,-0.3),(0,0.3),(0.19,0.3),(0.19,0.76),(0.53,0.76),(0.53,0.3),(2.61,0.3),(2.61,0.76),(2.95,0.76),(2.95,0.3),(5.085,0.3),(5.085,0.855),(5.315,0.855),(5.315,0.3),(6.72,0.3),(6.72,-0.3)],
  [(5.085,2.53),(5.085,3.62),(0,3.62),(0,4.22),(6.72,4.22),(6.72,3.62),(5.315,3.62),(5.315,2.53)])
R(gf180mcu_fd_sc_mcu7t5v0_, dualgate, [(-0.28,-0.28,7,4.2)])
R(gf180mcu_fd_sc_mcu7t5v0_, v5_xtor, [(0,0,6.72,3.92)])
R(gf180mcu_fd_sc_mcu7t5v0_, lvpwell, [(-0.43,-0.43,7.15,1.76)])
gf180mcu_fd_sc_mcu7t5v0_.add(gdstk.Label('A3', (3.08,2.52), layer=34, texttype=10))
gf180mcu_fd_sc_mcu7t5v0_.add(gdstk.Label('A4', (4.2,2.52), layer=34, texttype=10))
gf180mcu_fd_sc_mcu7t5v0_.add(gdstk.Label('VDD', (3.64,3.94), layer=34, texttype=10))
gf180mcu_fd_sc_mcu7t5v0_.add(gdstk.Label('VSS', (3.64,-0.02), layer=34, texttype=10))
gf180mcu_fd_sc_mcu7t5v0_.add(gdstk.Label('Z', (6.44,1.96), layer=34, texttype=10))
gf180mcu_fd_sc_mcu7t5v0_.add(gdstk.Label('A1', (0.84,1.96), layer=34, texttype=10))
gf180mcu_fd_sc_mcu7t5v0_.add(gdstk.Label('A2', (1.96,2.52), layer=34, texttype=10))
gf180mcu_fd_sc_mcu7t5v0_.add(gdstk.Label('& Vendor GLOBALFOUNDRIES', (0,2), layer=63, texttype=63))
gf180mcu_fd_sc_mcu7t5v0_.add(gdstk.Label('& Product GF018hv5v_mcu_sc7', (0,1.5), layer=63, texttype=63))
gf180mcu_fd_sc_mcu7t5v0_.add(gdstk.Label('& Version 2015q2v1', (0,1), layer=63, texttype=63))
gf180mcu_fd_sc_mcu7t5v0_.add(gdstk.Label('& Metric 1.00', (0,0.5), layer=63, texttype=63))
gf180mcu_fd_sc_mcu7t5v0_.add(gdstk.Label('VNW', (0.345,3.92), layer=21, texttype=10))
gf180mcu_fd_sc_mcu7t5v0_.add(gdstk.Label('VPW', (0.34,-0.085), layer=204, texttype=10))

lib.write_gds('gf180mcu_fd_sc_mcu7t5v0__or4_1.gds')
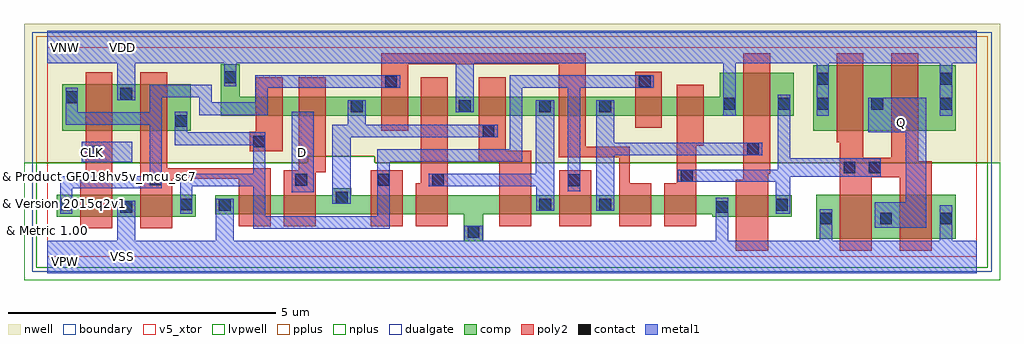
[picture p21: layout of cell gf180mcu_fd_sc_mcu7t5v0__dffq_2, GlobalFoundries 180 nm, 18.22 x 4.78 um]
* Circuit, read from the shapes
.subckt gf180mcu_fd_sc_mcu7t5v0__dffq_2 CLK D Q VDD VNW VSS
XM1 VSS CLK n1 VSUBS nfet_05v0 w=0.405u l=0.6u
XM2 n2 n1 VSS VSUBS nfet_05v0 w=0.405u l=0.6u
XM3 n3 n1 VSS VSUBS nfet_05v0 w=0.36u l=0.6u
XM4 n4 D n3 VSUBS nfet_05v0 w=0.36u l=0.6u
XM5 n5 n2 n4 VSUBS nfet_05v0 w=0.36u l=0.6u
XM6 VSS n6 n5 VSUBS nfet_05v0 w=0.36u l=0.6u
XM7 n6 n4 VSS VSUBS nfet_05v0 w=0.36u l=0.6u
XM8 n7 n2 n6 VSUBS nfet_05v0 w=0.36u l=0.6u
XM9 n8 n1 n7 VSUBS nfet_05v0 w=0.36u l=0.6u
XM10 VSS n9 n8 VSUBS nfet_05v0 w=0.36u l=0.6u
XM11 n9 n7 VSS VSUBS nfet_05v0 w=0.4u l=0.6u
XM12 Q n9 VSS VSUBS nfet_05v0 w=0.82u l=0.6u m=2
XM13 VDD CLK n1 VNW pfet_05v0 w=0.865u l=0.5u
XM14 n2 n1 VDD VNW pfet_05v0 w=0.865u l=0.5u
XM15 n10 n2 VDD VNW pfet_05v0 w=0.36u l=0.5u
XM16 n4 D n10 VNW pfet_05v0 w=0.36u l=0.5u
XM17 n11 n1 n4 VNW pfet_05v0 w=0.36u l=0.5u
XM18 VDD n6 n11 VNW pfet_05v0 w=0.36u l=0.5u
XM19 n6 n4 VDD VNW pfet_05v0 w=0.36u l=0.5u
XM20 n7 n1 n6 VNW pfet_05v0 w=0.36u l=0.5u
XM21 n12 n2 n7 VNW pfet_05v0 w=0.36u l=0.5u
XM22 VDD n9 n12 VNW pfet_05v0 w=0.36u l=0.5u
XM23 n9 n7 VDD VNW pfet_05v0 w=0.8u l=0.5u
XM24 Q n9 VDD VNW pfet_05v0 w=1.22u l=0.5u m=2
.ends

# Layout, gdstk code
import gdstk
lib = gdstk.Library(unit=1e-6, precision=1e-09)
def R(c, l, rs):  # rectangles x0, y0, x1, y1
    for r in rs: c.add(gdstk.rectangle(r[:2], r[2:], *l))
def A(c, l, x, y, w, h, nx, ny, dx, dy):  # array of equal rectangles
    R(c, l, [(x+i*dx, y+j*dy, x+i*dx+w, y+j*dy+h) for i in range(nx) for j in range(ny)])
def P(c, l, *ps):  # polygons
    for p in ps: c.add(gdstk.Polygon(p, *l))
boundary = (0, 0)
nwell = (21, 0)
comp = (22, 0)
poly2 = (30, 0)
pplus = (31, 0)
nplus = (32, 0)
contact = (33, 0)
metal1 = (34, 0)
dualgate = (55, 0)
v5_xtor = (112, 1)
lvpwell = (204, 0)

gf180mcu_fd_sc_mcu7t5v0_ = lib.new_cell('gf180mcu_fd_sc_mcu7t5v0__dffq_2')
R(gf180mcu_fd_sc_mcu7t5v0_, boundary, [(0,0,17.36,3.92)])
P(gf180mcu_fd_sc_mcu7t5v0_, nwell, [(-0.43,1.76),(-0.43,4.35),(17.79,4.35),(17.79,1.76),(6.12,1.76),(6.12,1.885),(4.865,1.885),(4.865,1.76)])
R(gf180mcu_fd_sc_mcu7t5v0_, comp, [(14.36,0.34,16.96,1.16), (0.18,0.755,2.78,1.16), (0.28,2.36,2.68,3.225), (14.3,2.36,16.96,3.58)])
P(gf180mcu_fd_sc_mcu7t5v0_, comp, [(7.78,0.29),(7.78,0.795),(3.14,0.795),(3.14,1.155),(5.32,1.155),(5.32,1.285),(5.68,1.285),(5.68,1.155),(13.9,1.155),(13.9,0.755),(12.42,0.755),(12.42,0.795),(8.14,0.795),(8.14,0.29)],
  [(3.24,2.635),(3.24,3.6),(3.6,3.6),(3.6,2.995),(12.56,2.995),(12.56,3.435),(13.94,3.435),(13.94,2.635)])
R(gf180mcu_fd_sc_mcu7t5v0_, poly2, [(6.04,0.575,6.64,1.62), (9.56,0.575,10.16,1.615), (10.98,2.415,11.48,3.455)])
P(gf180mcu_fd_sc_mcu7t5v0_, poly2, [(0.62,0.535),(0.62,1.44),(0.72,1.44),(0.72,3.45),(1.22,3.45),(1.22,0.535)],
  [(1.74,0.535),(1.74,3.45),(2.24,3.45),(2.24,1.66),(4.18,1.66),(4.18,0.575),(3.58,0.575),(3.58,1.46),(2.34,1.46),(2.34,0.535)],
  [(3.78,1.975),(3.78,2.335),(3.9,2.335),(3.9,3.36),(4.4,3.36),(4.4,1.975)],
  [(4.42,0.575),(4.42,1.62),(4.7,1.62),(4.7,3.36),(5.2,3.36),(5.2,1.585),(5.02,1.585),(5.02,0.575)],
  [(6.88,0.575),(6.88,1.375),(6.98,1.375),(6.98,3.36),(7.48,3.36),(7.48,0.575)],
  [(8.44,0.575),(8.44,1.78),(8.06,1.78),(8.06,3.36),(8.56,3.36),(8.56,1.98),(9.04,1.98),(9.04,0.575)],
  [(10.68,0.575),(10.68,1.86),(9.555,1.86),(9.555,3.6),(6.74,3.6),(6.74,2.355),(6.24,2.355),(6.24,3.8),(10.055,3.8),(10.055,2.06),(10.88,2.06),(10.88,1.375),(11.28,1.375),(11.28,0.575)],
  [(11.52,0.575),(11.52,1.375),(11.76,1.375),(11.76,3.215),(12.26,3.215),(12.26,2.08),(12.12,2.08),(12.12,0.575)],
  [(12.86,0.12),(12.86,1.44),(13,1.44),(13,3.8),(13.5,3.8),(13.5,1.555),(13.46,1.555),(13.46,0.12)],
  [(14.8,0.12),(14.8,2.14),(14.74,2.14),(14.74,3.8),(15.24,3.8),(15.24,1.85),(15.76,1.85),(15.76,3.8),(16.26,3.8),(16.26,1.785),(16.52,1.785),(16.52,0.12),(15.92,0.12),(15.92,1.49),(15.4,1.49),(15.4,0.12)])
P(gf180mcu_fd_sc_mcu7t5v0_, pplus, [(-0.2,1.76),(-0.2,4.12),(17.56,4.12),(17.56,1.76),(6.12,1.76),(6.12,1.885),(4.865,1.885),(4.865,1.76)])
P(gf180mcu_fd_sc_mcu7t5v0_, nplus, [(-0.2,-0.2),(-0.2,1.76),(4.865,1.76),(4.865,1.885),(6.12,1.885),(6.12,1.76),(17.56,1.76),(17.56,-0.2)])
A(gf180mcu_fd_sc_mcu7t5v0_, contact, 14.43, 0.61, 0.22, 0.22, 3, 1, 1.12, 0)
R(gf180mcu_fd_sc_mcu7t5v0_, contact, [(7.85,0.36,8.07,0.58), (1.37,0.825,1.59,1.045), (12.49,0.825,12.71,1.045), (3.21,0.865,3.43,1.085), (9.19,0.865,9.41,1.085), (10.31,0.865,10.53,1.085), (13.61,0.865,13.83,1.085), (0.25,0.87,0.47,1.09), (2.49,0.87,2.71,1.09), (5.39,0.995,5.61,1.215), (7.19,1.325,7.41,1.545), (9.725,1.325,9.945,1.545), (4.635,1.33,4.855,1.55), (6.17,1.33,6.39,1.55), (1.92,1.34,2.14,1.56), (11.83,1.405,12.05,1.625), (14.87,1.56,15.09,1.78), (15.34,1.56,15.56,1.78), (0.79,1.855,1.01,2.075), (13.07,1.9,13.29,2.12), (3.85,2.045,4.07,2.265), (8.13,2.245,8.35,2.465), (2.39,2.43,2.61,2.65), (5.67,2.705,5.89,2.925), (7.69,2.705,7.91,2.925), (9.185,2.705,9.405,2.925), (10.31,2.705,10.53,2.925), (12.63,2.75,12.85,2.97), (13.65,2.75,13.87,2.97), (14.37,2.75,14.59,2.97), (15.39,2.75,15.61,2.97), (16.67,2.75,16.89,2.97), (0.35,2.87,0.57,3.09), (1.37,2.935,1.59,3.155), (6.31,3.165,6.53,3.385), (11.05,3.165,11.27,3.385), (14.37,3.22,14.59,3.44), (16.67,3.22,16.89,3.44), (3.31,3.245,3.53,3.465)])
R(gf180mcu_fd_sc_mcu7t5v0_, metal1, [(4.57,1.21,4.975,2.71), (0.65,1.77,1.59,2.15)])
P(gf180mcu_fd_sc_mcu7t5v0_, metal1, [(0.245,0.81),(0.245,1.51),(1.915,1.51),(1.915,2.47),(0.345,2.47),(0.345,3.155),(0.575,3.155),(0.575,2.7),(1.915,2.7),(1.915,3.215),(3.075,3.215),(3.075,2.885),(3.89,2.885),(3.89,3.39),(6.59,3.39),(6.59,3.16),(4.12,3.16),(4.12,2.65),(2.845,2.65),(2.845,2.98),(2.145,2.98),(2.145,1.28),(0.475,1.28),(0.475,0.81)],
  [(5.325,0.99),(5.325,2.47),(5.61,2.47),(5.61,2.93),(5.95,2.93),(5.95,2.47),(8.41,2.47),(8.41,2.24),(5.67,2.24),(5.67,0.99)],
  [(9.13,0.86),(9.13,1.32),(7.13,1.32),(7.13,1.55),(9.125,1.55),(9.125,2.93),(9.47,2.93),(9.47,0.86)],
  [(3.845,0.53),(3.845,1.325),(2.715,1.325),(2.715,0.81),(2.485,0.81),(2.485,1.555),(3.845,1.555),(3.845,2.09),(2.385,2.09),(2.385,2.71),(2.615,2.71),(2.615,2.325),(4.075,2.325),(4.075,0.76),(6.165,0.76),(6.165,2.01),(8.64,2.01),(8.64,3.39),(11.33,3.39),(11.33,3.16),(9.95,3.16),(9.95,1.225),(9.72,1.225),(9.72,3.16),(8.87,3.16),(8.87,1.78),(6.395,1.78),(6.395,0.53)],
  [(10.25,0.86),(10.25,2.93),(10.59,2.93),(10.59,2.13),(13.35,2.13),(13.35,1.895),(10.59,1.895),(10.59,0.86)],
  [(13.605,0.805),(13.605,1.4),(11.77,1.4),(11.77,1.63),(13.645,1.63),(13.645,3.03),(13.875,3.03),(13.875,1.84),(15.565,1.84),(15.565,1.5),(13.87,1.5),(13.87,0.805)],
  [(15.45,0.55),(15.45,1.02),(16.03,1.02),(16.03,2.33),(15.33,2.33),(15.33,2.975),(16.41,2.975),(16.41,0.55)],
  [(0,-0.3),(0,0.3),(1.31,0.3),(1.31,1.05),(1.65,1.05),(1.65,0.3),(3.15,0.3),(3.15,1.09),(3.49,1.09),(3.49,0.3),(7.79,0.3),(7.79,0.585),(8.13,0.585),(8.13,0.3),(12.485,0.3),(12.485,1.105),(12.715,1.105),(12.715,0.3),(14.425,0.3),(14.425,0.89),(14.655,0.89),(14.655,0.3),(16.665,0.3),(16.665,0.97),(16.895,0.97),(16.895,0.3),(17.36,0.3),(17.36,-0.3)],
  [(12.625,2.635),(12.625,3.62),(7.97,3.62),(7.97,2.7),(7.63,2.7),(7.63,3.62),(3.535,3.62),(3.535,3.185),(3.305,3.185),(3.305,3.62),(1.65,3.62),(1.65,2.93),(1.31,2.93),(1.31,3.62),(0,3.62),(0,4.22),(17.36,4.22),(17.36,3.62),(16.895,3.62),(16.895,2.635),(16.665,2.635),(16.665,3.62),(14.595,3.62),(14.595,2.635),(14.365,2.635),(14.365,3.62),(12.855,3.62),(12.855,2.635)])
R(gf180mcu_fd_sc_mcu7t5v0_, dualgate, [(-0.28,-0.28,17.64,4.2)])
R(gf180mcu_fd_sc_mcu7t5v0_, v5_xtor, [(0,0,17.36,3.92)])
P(gf180mcu_fd_sc_mcu7t5v0_, lvpwell, [(-0.43,-0.43),(-0.43,1.76),(4.865,1.76),(4.865,1.885),(6.12,1.885),(6.12,1.76),(17.79,1.76),(17.79,-0.43)])
gf180mcu_fd_sc_mcu7t5v0_.add(gdstk.Label('D', (4.76,1.96), layer=34, texttype=10))
gf180mcu_fd_sc_mcu7t5v0_.add(gdstk.Label('VDD', (1.4,3.92), layer=34, texttype=10))
gf180mcu_fd_sc_mcu7t5v0_.add(gdstk.Label('VSS', (1.4,0), layer=34, texttype=10))
gf180mcu_fd_sc_mcu7t5v0_.add(gdstk.Label('CLK', (0.84,1.96), layer=34, texttype=10))
gf180mcu_fd_sc_mcu7t5v0_.add(gdstk.Label('Q', (15.96,2.52), layer=34, texttype=10))
gf180mcu_fd_sc_mcu7t5v0_.add(gdstk.Label('& Vendor GLOBALFOUNDRIES', (0,2), layer=63, texttype=63))
gf180mcu_fd_sc_mcu7t5v0_.add(gdstk.Label('& Product GF018hv5v_mcu_sc7', (0,1.5), layer=63, texttype=63))
gf180mcu_fd_sc_mcu7t5v0_.add(gdstk.Label('& Version 2015q2v1', (0,1), layer=63, texttype=63))
gf180mcu_fd_sc_mcu7t5v0_.add(gdstk.Label('& Metric 1.00', (0,0.5), layer=63, texttype=63))
gf180mcu_fd_sc_mcu7t5v0_.add(gdstk.Label('VNW', (0.345,3.92), layer=21, texttype=10))
gf180mcu_fd_sc_mcu7t5v0_.add(gdstk.Label('VPW', (0.34,-0.085), layer=204, texttype=10))

lib.write_gds('gf180mcu_fd_sc_mcu7t5v0__dffq_2.gds')
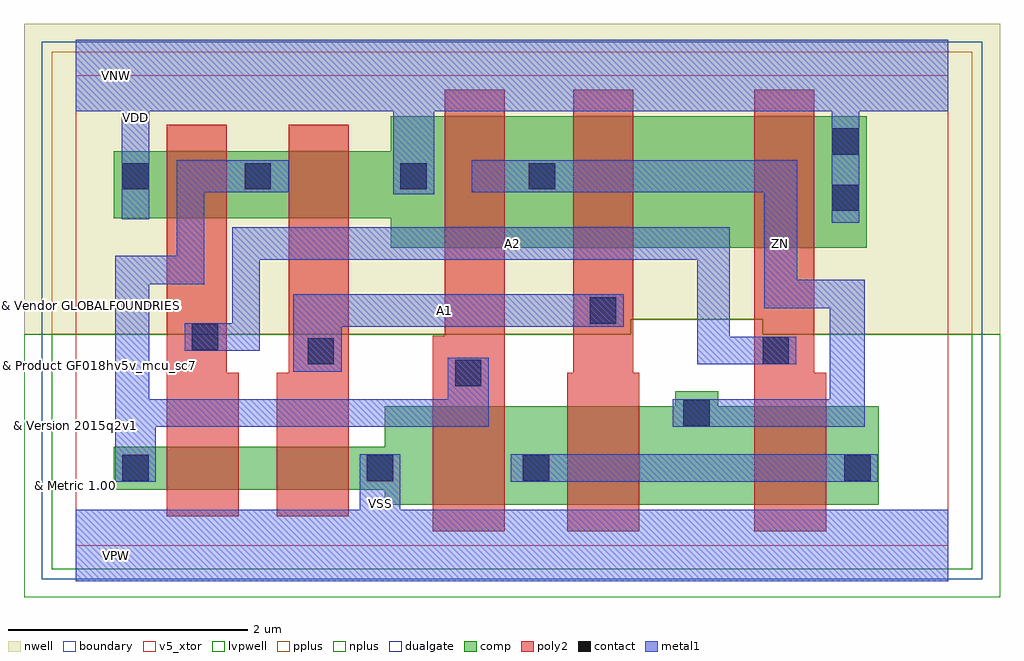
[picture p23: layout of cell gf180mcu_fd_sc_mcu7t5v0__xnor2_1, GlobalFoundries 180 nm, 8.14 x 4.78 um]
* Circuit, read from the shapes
.subckt gf180mcu_fd_sc_mcu7t5v0__xnor2_1 A1 A2 VDD VNW VSS ZN
XM1 n1 A2 n2 VSUBS nfet_05v0 w=0.36u l=0.6u
XM2 VSS A1 n1 VSUBS nfet_05v0 w=0.36u l=0.6u
XM3 n3 n2 VSS VSUBS nfet_05v0 w=0.82u l=0.6u
XM4 ZN A1 n3 VSUBS nfet_05v0 w=0.82u l=0.6u
XM5 n3 A2 ZN VSUBS nfet_05v0 w=0.82u l=0.6u
XM6 n2 A2 VDD VNW pfet_05v0 w=0.56u l=0.5u
XM7 VDD A1 n2 VNW pfet_05v0 w=0.56u l=0.5u
XM8 ZN n2 VDD VNW pfet_05v0 w=1.095u l=0.5u
XM9 n4 A1 ZN VNW pfet_05v0 w=1.095u l=0.5u
XM10 VDD A2 n4 VNW pfet_05v0 w=1.095u l=0.5u
.ends

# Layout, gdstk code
import gdstk
lib = gdstk.Library(unit=1e-6, precision=1e-09)
def R(c, l, rs):  # rectangles x0, y0, x1, y1
    for r in rs: c.add(gdstk.rectangle(r[:2], r[2:], *l))
def P(c, l, *ps):  # polygons
    for p in ps: c.add(gdstk.Polygon(p, *l))
boundary = (0, 0)
nwell = (21, 0)
comp = (22, 0)
poly2 = (30, 0)
pplus = (31, 0)
nplus = (32, 0)
contact = (33, 0)
metal1 = (34, 0)
dualgate = (55, 0)
v5_xtor = (112, 1)
lvpwell = (204, 0)

gf180mcu_fd_sc_mcu7t5v0_ = lib.new_cell('gf180mcu_fd_sc_mcu7t5v0__xnor2_1')
R(gf180mcu_fd_sc_mcu7t5v0_, boundary, [(0,0,7.28,3.92)])
P(gf180mcu_fd_sc_mcu7t5v0_, nwell, [(-0.43,1.76),(-0.43,4.35),(7.71,4.35),(7.71,1.76),(5.73,1.76),(5.73,1.885),(4.63,1.885),(4.63,1.76)])
P(gf180mcu_fd_sc_mcu7t5v0_, comp, [(2.63,2.485),(2.63,2.73),(0.32,2.73),(0.32,3.29),(2.63,3.29),(2.63,3.58),(6.6,3.58),(6.6,2.485)],
  [(2.58,0.34),(2.58,0.465),(0.32,0.465),(0.32,0.825),(2.58,0.825),(2.58,1.16),(5,1.16),(5,1.285),(5.36,1.285),(5.36,1.16),(6.7,1.16),(6.7,0.34)])
P(gf180mcu_fd_sc_mcu7t5v0_, poly2, [(0.76,0.245),(0.76,3.51),(1.26,3.51),(1.26,1.44),(1.36,1.44),(1.36,0.245)],
  [(1.68,0.245),(1.68,1.44),(1.78,1.44),(1.78,3.51),(2.28,3.51),(2.28,0.245)],
  [(2.98,0.12),(2.98,1.75),(3.08,1.75),(3.08,3.8),(3.58,3.8),(3.58,0.12)],
  [(4.1,0.12),(4.1,1.44),(4.15,1.44),(4.15,3.8),(4.65,3.8),(4.65,1.44),(4.7,1.44),(4.7,0.12)],
  [(5.66,0.12),(5.66,3.8),(6.16,3.8),(6.16,1.44),(6.26,1.44),(6.26,0.12)])
P(gf180mcu_fd_sc_mcu7t5v0_, pplus, [(-0.2,1.76),(-0.2,4.12),(7.48,4.12),(7.48,1.76),(5.73,1.76),(5.73,1.885),(4.63,1.885),(4.63,1.76)])
P(gf180mcu_fd_sc_mcu7t5v0_, nplus, [(-0.2,-0.2),(-0.2,1.76),(4.63,1.76),(4.63,1.885),(5.73,1.885),(5.73,1.76),(7.48,1.76),(7.48,-0.2)])
R(gf180mcu_fd_sc_mcu7t5v0_, contact, [(0.39,0.535,0.61,0.755), (2.43,0.535,2.65,0.755), (3.73,0.535,3.95,0.755), (6.41,0.535,6.63,0.755), (5.07,0.995,5.29,1.215), (3.165,1.33,3.385,1.55), (1.935,1.51,2.155,1.73), (5.73,1.515,5.95,1.735), (0.97,1.63,1.19,1.85), (4.29,1.85,4.51,2.07), (6.31,2.79,6.53,3.01), (0.39,2.97,0.61,3.19), (1.41,2.97,1.63,3.19), (2.71,2.97,2.93,3.19), (3.78,2.97,4,3.19), (6.31,3.26,6.53,3.48)])
R(gf180mcu_fd_sc_mcu7t5v0_, metal1, [(3.63,0.53,6.69,0.76)])
P(gf180mcu_fd_sc_mcu7t5v0_, metal1, [(0.33,0.53),(0.33,2.415),(0.845,2.415),(0.845,3.215),(1.78,3.215),(1.78,2.945),(1.075,2.945),(1.075,2.18),(0.615,2.18),(0.615,1.22),(3.105,1.22),(3.105,1.565),(3.445,1.565),(3.445,0.99),(0.67,0.99),(0.67,0.53)],
  [(1.815,1.45),(1.815,2.095),(4.57,2.095),(4.57,1.825),(2.22,1.825),(2.22,1.45)],
  [(5.185,1.51),(5.185,2.385),(1.535,2.385),(1.535,1.625),(0.91,1.625),(0.91,1.855),(1.305,1.855),(1.305,2.655),(5.455,2.655),(5.455,1.74),(6.01,1.74),(6.01,1.51)],
  [(4.98,0.99),(4.98,1.22),(6.29,1.22),(6.29,1.98),(5.745,1.98),(5.745,2.945),(3.305,2.945),(3.305,3.215),(6.02,3.215),(6.02,2.215),(6.58,2.215),(6.58,0.99)],
  [(0,-0.3),(0,0.3),(2.37,0.3),(2.37,0.76),(2.71,0.76),(2.71,0.3),(7.28,0.3),(7.28,-0.3)],
  [(6.305,2.69),(6.305,3.62),(2.99,3.62),(2.99,2.93),(2.65,2.93),(2.65,3.62),(0.615,3.62),(0.615,2.72),(0.385,2.72),(0.385,3.62),(0,3.62),(0,4.22),(7.28,4.22),(7.28,3.62),(6.535,3.62),(6.535,2.69)])
R(gf180mcu_fd_sc_mcu7t5v0_, dualgate, [(-0.28,-0.28,7.56,4.2)])
R(gf180mcu_fd_sc_mcu7t5v0_, v5_xtor, [(0,0,7.28,3.92)])
P(gf180mcu_fd_sc_mcu7t5v0_, lvpwell, [(-0.43,-0.43),(-0.43,1.76),(4.63,1.76),(4.63,1.885),(5.73,1.885),(5.73,1.76),(7.71,1.76),(7.71,-0.43)])
gf180mcu_fd_sc_mcu7t5v0_.add(gdstk.Label('VDD', (0.5,3.57), layer=34, texttype=10))
gf180mcu_fd_sc_mcu7t5v0_.add(gdstk.Label('VSS', (2.54,0.35), layer=34, texttype=10))
gf180mcu_fd_sc_mcu7t5v0_.add(gdstk.Label('ZN', (5.88,2.52), layer=34, texttype=10))
gf180mcu_fd_sc_mcu7t5v0_.add(gdstk.Label('A1', (3.08,1.96), layer=34, texttype=10))
gf180mcu_fd_sc_mcu7t5v0_.add(gdstk.Label('A2', (3.64,2.52), layer=34, texttype=10))
gf180mcu_fd_sc_mcu7t5v0_.add(gdstk.Label('& Vendor GLOBALFOUNDRIES', (0,2), layer=63, texttype=63))
gf180mcu_fd_sc_mcu7t5v0_.add(gdstk.Label('& Product GF018hv5v_mcu_sc7', (0,1.5), layer=63, texttype=63))
gf180mcu_fd_sc_mcu7t5v0_.add(gdstk.Label('& Version 2015q2v1', (0,1), layer=63, texttype=63))
gf180mcu_fd_sc_mcu7t5v0_.add(gdstk.Label('& Metric 1.00', (0,0.5), layer=63, texttype=63))
gf180mcu_fd_sc_mcu7t5v0_.add(gdstk.Label('VNW', (0.345,3.92), layer=21, texttype=10))
gf180mcu_fd_sc_mcu7t5v0_.add(gdstk.Label('VPW', (0.34,-0.085), layer=204, texttype=10))

lib.write_gds('gf180mcu_fd_sc_mcu7t5v0__xnor2_1.gds')
